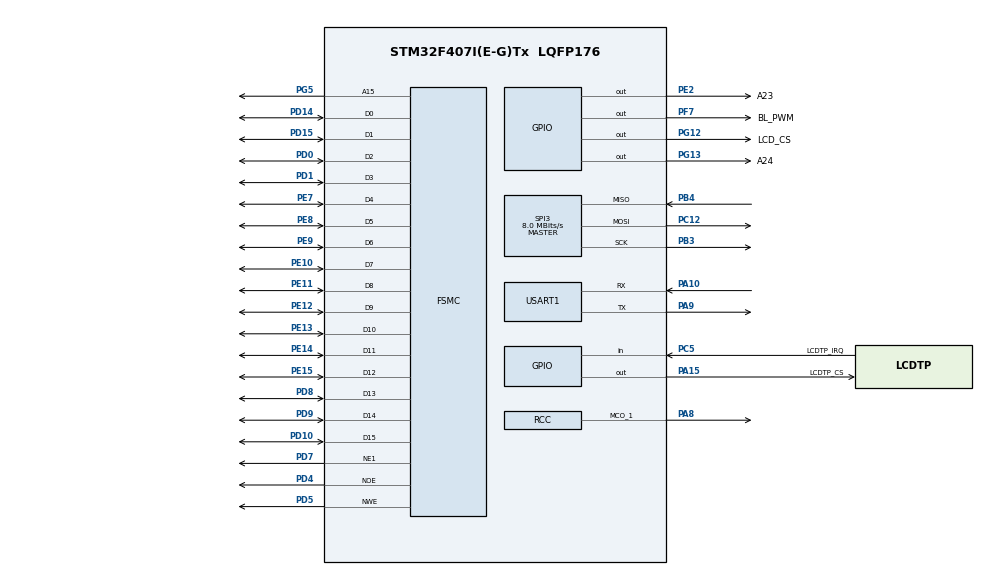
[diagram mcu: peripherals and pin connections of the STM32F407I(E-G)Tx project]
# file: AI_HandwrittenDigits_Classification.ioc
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FSMC.BusTurnAroundDuration1=0
FSMC.DataSetupTime1=40
Mcu.Family=STM32F4
Mcu.Name=STM32F407I(E-G)Tx
Mcu.Package=LQFP176
NVIC.PriorityGroup=NVIC_PRIORITYGROUP_4
NVIC.USART1_IRQn=true\:0\:0\:false\:false\:true\:true\:true
PA10.Mode=Asynchronous
PA10.Signal=USART1_RX
PA15.GPIO_Label=LCDTP_CS
PA15.Signal=GPIO_Output
PA8.Mode=Clock-out-1
PA8.Signal=RCC_MCO_1
PA9.Mode=Asynchronous
PA9.Signal=USART1_TX
PB3.Mode=Full_Duplex_Master
PB3.Signal=SPI3_SCK
PB4.Mode=Full_Duplex_Master
PB4.Signal=SPI3_MISO
PC12.Mode=Full_Duplex_Master
PC12.Signal=SPI3_MOSI
PC5.GPIO_Label=LCDTP_IRQ
PC5.Signal=GPIO_Input
PD0.Signal=FSMC_D2_DA2
PD1.Signal=FSMC_D3_DA3
PD10.Signal=FSMC_D15_DA15
PD14.Signal=FSMC_D0_DA0
PD15.Signal=FSMC_D1_DA1
PD4.Signal=FSMC_NOE
PD5.Signal=FSMC_NWE
PD7.Mode=NorPsramChipSelect1_1
PD7.Signal=FSMC_NE1
PD8.Signal=FSMC_D13_DA13
PD9.Signal=FSMC_D14_DA14
PE10.Signal=FSMC_D7_DA7
PE11.Signal=FSMC_D8_DA8
PE12.Signal=FSMC_D9_DA9
PE13.Signal=FSMC_D10_DA10
PE14.Signal=FSMC_D11_DA11
PE15.Signal=FSMC_D12_DA12
PE2.GPIO_Label=A23
PE2.PinState=GPIO_PIN_SET
PE2.Signal=GPIO_Output
PE7.Signal=FSMC_D4_DA4
PE8.Signal=FSMC_D5_DA5
PE9.Signal=FSMC_D6_DA6
PF7.GPIO_Label=BL_PWM
PF7.PinState=GPIO_PIN_SET
PF7.Signal=GPIO_Output
PG12.GPIO_Label=LCD_CS
PG12.Signal=GPIO_Output
PG13.GPIO_Label=A24
PG13.PinState=GPIO_PIN_SET
PG13.Signal=GPIO_Output
PG5.Signal=FSMC_A15
PH0-OSC_IN.Mode=HSE-External-Oscillator
PH0-OSC_IN.Signal=RCC_OSC_IN
PH1-OSC_OUT.Mode=HSE-External-Oscillator
PH1-OSC_OUT.Signal=RCC_OSC_OUT
ProjectManager.HeapSize=0x200
ProjectManager.StackSize=0x400
ProjectManager.TargetToolchain=STM32CubeIDE
RCC.AHBFreq_Value=16000000
RCC.APB1Freq_Value=16000000
RCC.APB2Freq_Value=16000000
RCC.CortexFreq_Value=16000000
RCC.HSE_VALUE=25000000
RCC.HSI_VALUE=16000000
RCC.LSE_VALUE=32768
RCC.SYSCLKFreq_VALUE=16000000
RCC.VCOOutputFreq_Value=192000000
SH.FSMC_A15.0=FSMC_A15,A15_1
SH.FSMC_D0_DA0.0=FSMC_D0,16b-d1
SH.FSMC_D10_DA10.0=FSMC_D10,16b-d1
SH.FSMC_D11_DA11.0=FSMC_D11,16b-d1
SH.FSMC_D12_DA12.0=FSMC_D12,16b-d1
SH.FSMC_D13_DA13.0=FSMC_D13,16b-d1
SH.FSMC_D14_DA14.0=FSMC_D14,16b-d1
SH.FSMC_D15_DA15.0=FSMC_D15,16b-d1
SH.FSMC_D1_DA1.0=FSMC_D1,16b-d1
SH.FSMC_D2_DA2.0=FSMC_D2,16b-d1
SH.FSMC_D3_DA3.0=FSMC_D3,16b-d1
SH.FSMC_D4_DA4.0=FSMC_D4,16b-d1
SH.FSMC_D5_DA5.0=FSMC_D5,16b-d1
SH.FSMC_D6_DA6.0=FSMC_D6,16b-d1
SH.FSMC_D7_DA7.0=FSMC_D7,16b-d1
SH.FSMC_D8_DA8.0=FSMC_D8,16b-d1
SH.FSMC_D9_DA9.0=FSMC_D9,16b-d1
SH.FSMC_NOE.0=FSMC_NOE,Lcd1
SH.FSMC_NWE.0=FSMC_NWE,Lcd1
SPI3.CalculateBaudRate=8.0 MBits/s
SPI3.Direction=SPI_DIRECTION_2LINES
SPI3.Mode=SPI_MODE_MASTER
SPI3.VirtualType=VM_MASTER
STMicroelectronics.X-CUBE-AI.4.0.0.ApplicationCcArtificialOoIntelligenceJjApplication=ApplicationTemplate
STMicroelectronics.X-CUBE-AI.4.0.0.ArtificialOoIntelligenceJjApplication.cmp_version0=4.0.0
STMicroelectronics.X-CUBE-AI.4.0.0.ArtificialOoIntelligenceJjApplication.component0=Artificial Intelligence
STMicroelectronics.X-CUBE-AI.4.0.0.ArtificialOoIntelligenceJjApplication.description0=AI Application,Application Template
STMicroelectronics.X-CUBE-AI.4.0.0.ArtificialOoIntelligenceJjApplication.diagnostic0=This component requires one or more component from the same or other SW pack to operate correctly
STMicroelectronics.X-CUBE-AI.4.0.0.ArtificialOoIntelligenceJjApplication.documentation0=Documentation/index.html
STMicroelectronics.X-CUBE-AI.4.0.0.ArtificialOoIntelligenceJjApplication.group0=Application
STMicroelectronics.X-CUBE-AI.4.0.0.ArtificialOoIntelligenceJjApplication.paramName0=ApplicationCcArtificialOoIntelligenceJjApplication
STMicroelectronics.X-CUBE-AI.4.0.0.ArtificialOoIntelligenceJjApplication.sevirity0=minor
STMicroelectronics.X-CUBE-AI.4.0.0.ArtificialOoIntelligenceJjApplication.variant0=ApplicationTemplate
STMicroelectronics.X-CUBE-AI.4.0.0.ArtificialOoIntelligenceJjApplication_bundle=Application
STMicroelectronics.X-CUBE-AI.4.0.0.ArtificialOoIntelligenceJjApplication_class=ArtificialOoIntelligence
STMicroelectronics.X-CUBE-AI.4.0.0.ArtificialOoIntelligenceJjApplication_name=X-CUBE-AI
STMicroelectronics.X-CUBE-AI.4.0.0.ArtificialOoIntelligenceJjApplication_size=1
STMicroelectronics.X-CUBE-AI.4.0.0.ArtificialOoIntelligenceJjApplication_vendor=STMicroelectronics
STMicroelectronics.X-CUBE-AI.4.0.0.ArtificialOoIntelligenceJjApplication_version=4.0.0
STMicroelectronics.X-CUBE-AI.4.0.0.ArtificialOoIntelligenceJjXAaCUBEAaAI.cmp_version0=4.0.0
STMicroelectronics.X-CUBE-AI.4.0.0.ArtificialOoIntelligenceJjXAaCUBEAaAI.cmp_version1=4.0.0
STMicroelectronics.X-CUBE-AI.4.0.0.ArtificialOoIntelligenceJjXAaCUBEAaAI.component0=Artificial Intelligence
STMicroelectronics.X-CUBE-AI.4.0.0.ArtificialOoIntelligenceJjXAaCUBEAaAI.component1=Artificial Intelligence
STMicroelectronics.X-CUBE-AI.4.0.0.ArtificialOoIntelligenceJjXAaCUBEAaAI.componentDoc0=nofile
STMicroelectronics.X-CUBE-AI.4.0.0.ArtificialOoIntelligenceJjXAaCUBEAaAI.description0=AI Core,Artificial Intelligence for STM32
STMicroelectronics.X-CUBE-AI.4.0.0.ArtificialOoIntelligenceJjXAaCUBEAaAI.description1=AI Application,Application Template
STMicroelectronics.X-CUBE-AI.4.0.0.ArtificialOoIntelligenceJjXAaCUBEAaAI.diagnostic0=This component should operate correctly.
STMicroelectronics.X-CUBE-AI.4.0.0.ArtificialOoIntelligenceJjXAaCUBEAaAI.diagnostic1=This component requires one or more component from the same or other SW pack to operate correctly
STMicroelectronics.X-CUBE-AI.4.0.0.ArtificialOoIntelligenceJjXAaCUBEAaAI.documentation0=Documentation/index.html
STMicroelectronics.X-CUBE-AI.4.0.0.ArtificialOoIntelligenceJjXAaCUBEAaAI.documentation1=Documentation/index.html
STMicroelectronics.X-CUBE-AI.4.0.0.ArtificialOoIntelligenceJjXAaCUBEAaAI.group0=Core
STMicroelectronics.X-CUBE-AI.4.0.0.ArtificialOoIntelligenceJjXAaCUBEAaAI.group1=Application
STMicroelectronics.X-CUBE-AI.4.0.0.ArtificialOoIntelligenceJjXAaCUBEAaAI.paramName0=XAaCUBEAaAICcArtificialOoIntelligenceJjCore
STMicroelectronics.X-CUBE-AI.4.0.0.ArtificialOoIntelligenceJjXAaCUBEAaAI.paramName1=ApplicationCcArtificialOoIntelligenceJjApplication
STMicroelectronics.X-CUBE-AI.4.0.0.ArtificialOoIntelligenceJjXAaCUBEAaAI.sevirity0=none
STMicroelectronics.X-CUBE-AI.4.0.0.ArtificialOoIntelligenceJjXAaCUBEAaAI.sevirity1=minor
STMicroelectronics.X-CUBE-AI.4.0.0.ArtificialOoIntelligenceJjXAaCUBEAaAI.variant1=ApplicationTemplate
STMicroelectronics.X-CUBE-AI.4.0.0.ArtificialOoIntelligenceJjXAaCUBEAaAI_bundle=X-CUBE-AI
STMicroelectronics.X-CUBE-AI.4.0.0.ArtificialOoIntelligenceJjXAaCUBEAaAI_class=ArtificialOoIntelligence
STMicroelectronics.X-CUBE-AI.4.0.0.ArtificialOoIntelligenceJjXAaCUBEAaAI_name=X-CUBE-AI
STMicroelectronics.X-CUBE-AI.4.0.0.ArtificialOoIntelligenceJjXAaCUBEAaAI_size=2
STMicroelectronics.X-CUBE-AI.4.0.0.ArtificialOoIntelligenceJjXAaCUBEAaAI_vendor=STMicroelectronics
STMicroelectronics.X-CUBE-AI.4.0.0.ArtificialOoIntelligenceJjXAaCUBEAaAI_version=4.0.0
STMicroelectronics.X-CUBE-AI.4.0.0.LatestDirectoryUsed-9fa8add1d17a329f3bc8a1bb6cbe9676fff839fc02631deaaa17ee1fde3ea9c4=C\:\\Users\\Prakashs\\Downloads
STMicroelectronics.X-CUBE-AI.4.0.0.ModelActualCompression-9fa8add1d17a329f3bc8a1bb6cbe9676fff839fc02631deaaa17ee1fde3ea9c4=0.0
STMicroelectronics.X-CUBE-AI.4.0.0.ModelCompression-9fa8add1d17a329f3bc8a1bb6cbe9676fff839fc02631deaaa17ee1fde3ea9c4=1
STMicroelectronics.X-CUBE-AI.4.0.0.ModelFlashOccupation-9fa8add1d17a329f3bc8a1bb6cbe9676fff839fc02631deaaa17ee1fde3ea9c4=407080
STMicroelectronics.X-CUBE-AI.4.0.0.ModelHashList=9fa8add1d17a329f3bc8a1bb6cbe9676fff839fc02631deaaa17ee1fde3ea9c4
STMicroelectronics.X-CUBE-AI.4.0.0.ModelKind-9fa8add1d17a329f3bc8a1bb6cbe9676fff839fc02631deaaa17ee1fde3ea9c4=KERAS
STMicroelectronics.X-CUBE-AI.4.0.0.ModelMacc-9fa8add1d17a329f3bc8a1bb6cbe9676fff839fc02631deaaa17ee1fde3ea9c4=101910
STMicroelectronics.X-CUBE-AI.4.0.0.ModelName-9fa8add1d17a329f3bc8a1bb6cbe9676fff839fc02631deaaa17ee1fde3ea9c4=digitclassification
STMicroelectronics.X-CUBE-AI.4.0.0.ModelNameList=digitclassification
STMicroelectronics.X-CUBE-AI.4.0.0.ModelRamOccupation-9fa8add1d17a329f3bc8a1bb6cbe9676fff839fc02631deaaa17ee1fde3ea9c4=552
STMicroelectronics.X-CUBE-AI.4.0.0.ModelStructureFile-9fa8add1d17a329f3bc8a1bb6cbe9676fff839fc02631deaaa17ee1fde3ea9c4=C\:\\Users\\Prakashs\\Downloads\\model_CNN.h5
STMicroelectronics.X-CUBE-AI.4.0.0.ModelType-9fa8add1d17a329f3bc8a1bb6cbe9676fff839fc02631deaaa17ee1fde3ea9c4=Model and Topology
STMicroelectronics.X-CUBE-AI.4.0.0.ModelWeightFile-9fa8add1d17a329f3bc8a1bb6cbe9676fff839fc02631deaaa17ee1fde3ea9c4=C\:\\Users\\Prakashs\\Downloads\\model_CNN.json
STMicroelectronics.X-CUBE-AI.4.0.0.XAaCUBEAaAICcArtificialOoIntelligenceJjCore=true
STMicroelectronics.X-CUBE-AI.4.0.0_ArtificialOoIntelligenceJjApplication_RteComponent0=\#define AI_ApplicationTemplate
STMicroelectronics.X-CUBE-AI.4.0.0_ArtificialOoIntelligenceJjApplication_RteComponentsize=1
STMicroelectronics.X-CUBE-AI.4.0.0_ArtificialOoIntelligenceJjXAaCUBEAaAI_RteComponentsize=0
STMicroelectronics.X-CUBE-AI.4.0.0_MwName0=X-CUBE-AI
STMicroelectronics.X-CUBE-AI.4.0.0_MwName1=Application
STMicroelectronics.X-CUBE-AI.4.0.0_NumberOfMw=2
STMicroelectronics.X-CUBE-AI.4.0.0_description=Artificial Intelligence
STMicroelectronics.X-CUBE-AI.4.0.0_license=SLA0048.txt
USART1.VirtualMode=VM_ASYNC
VP_CRC_VS_CRC.Mode=CRC_Activate
VP_STMicroelectronics.X-CUBE-AI_VS_ArtificialOoIntelligenceJjApplication_4.0.0.Mode=ArtificialOoIntelligenceJjApplication
VP_STMicroelectronics.X-CUBE-AI_VS_ArtificialOoIntelligenceJjXAaCUBEAaAI_4.0.0.Mode=ArtificialOoIntelligenceJjXAaCUBEAaAI
board=custom

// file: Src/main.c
/* USER CODE BEGIN Header */
/**
  ******************************************************************************
  * @file           : main.c
  * @brief          : Main program body
  ******************************************************************************
  * @attention
  *
  * <h2><center>&copy; Copyright (c) 2019 STMicroelectronics.
  * All rights reserved.</center></h2>
  *
  * This software component is licensed by ST under BSD 3-Clause license,
  * the "License"; You may not use this file except in compliance with the
  * License. You may obtain a copy of the License at:
  *                        opensource.org/licenses/BSD-3-Clause
  *
  ******************************************************************************
  */
/* USER CODE END Header */

#include "main.h"
#include "app_x-cube-ai.h"

/* USER CODE BEGIN Includes */
#include "stm32_lcd_bsp.h"
#include "touch_panel.h"
/* USER CODE END Includes */

/* USER CODE BEGIN PM */
#ifdef __GNUC__
  /* With GCC/RAISONANCE, small printf (option LD Linker->Libraries->Small printf
     set to 'Yes') calls __io_putchar() */
  #define PUTCHAR_PROTOTYPE int __io_putchar(int ch)
#else
  #define PUTCHAR_PROTOTYPE int fputc(int ch, FILE *f)
#endif /* __GNUC__ */
/* USER CODE END PM */

CRC_HandleTypeDef hcrc;

SPI_HandleTypeDef hspi3;

UART_HandleTypeDef huart1;

SRAM_HandleTypeDef hsram1;

/* USER CODE BEGIN PV */
uint16_t original_image[168*168];
uint8_t grayscale_image[28*28];
uint16_t resized_image[28*28];
uint16_t *ptToImage = &original_image;
uint16_t drawMenuNeeded = 0;
/* USER CODE END PV */

void SystemClock_Config(void);
static void MX_GPIO_Init(void);
static void MX_CRC_Init(void);
static void MX_FSMC_Init(void);
static void MX_SPI3_Init(void);
static void MX_USART1_UART_Init(void);
/* USER CODE BEGIN PFP */
void loadImageIntoMemory();
void convert_8Bit_Grayscale(uint16_t* buffer);
void ImageResize(uint8_t *srcImage, uint32_t srcW, uint32_t srcH,
                 uint32_t pixelSize, uint32_t roiX, uint32_t roiY,
                 uint32_t roiW, uint32_t roiH,  uint8_t *dstImage,
                 uint32_t dstW, uint32_t dstH);
void drawMenu();
/* USER CODE END PFP */

int main(void)
{
  /* USER CODE BEGIN 1 */
	uint16_t linenum = 0;
  /* USER CODE END 1 */

  /* MCU Configuration--------------------------------------------------------*/

  /* Reset of all peripherals, Initializes the Flash interface and the Systick. */
  HAL_Init();

  /* Configure the system clock */
  SystemClock_Config();

  /* Initialize all configured peripherals */
  MX_GPIO_Init();
  MX_CRC_Init();
  MX_FSMC_Init();
  MX_SPI3_Init();
  MX_USART1_UART_Init();
  MX_X_CUBE_AI_Init();
  /* USER CODE BEGIN 2 */
  /* Initialize the LCD */
  BSP_LCD_Init();
    /* Enable the LCD */
  BSP_LCD_DisplayOn();
    /* Touch Panel configuration */
  printf("LCD is on");
  TouchPanel_Calibrate();
  drawMenu();
  printf("touch calibrated");
  /* USER CODE END 2 */

  /* Infinite loop */
  while (1)
  {
    /* USER CODE BEGIN 3 */

	  	  	getDisplayPoint(&display, Read_Ads7846(), &matrix );
	  	    if(((display.y < 190) && (display.y >= 2)))
	  	    {
	  	      if((display.x >= 318) || (display.x < 2))
	  	      {}
	  	      else
	  	      {
	  	        BSP_LCD_FillCircle(display.x, display.y, 2);
	  	      }
	  	    }

	  	    if((HAL_GPIO_ReadPin(Push_button_GPIO_Port, Push_button_Pin))==GPIO_PIN_RESET)
	  	    {
	  	    	loadImageIntoMemory();
	  	    	ImageResize((uint8_t*)original_image, 168, 168, 2, 0, 0, 0, 0,(uint8_t*)resized_image, 28, 28);
	  	    	convert_8Bit_Grayscale((uint16_t*)resized_image);
	  	    	MX_X_CUBE_AI_Process();
	  	    }
  }
  /* USER CODE END 3 */
}

void SystemClock_Config(void)
{
	 RCC_OscInitTypeDef RCC_OscInitStruct;
	  RCC_ClkInitTypeDef RCC_ClkInitStruct;

	    /**Configure the main internal regulator output voltage
	    */
	  __HAL_RCC_PWR_CLK_ENABLE();

	  __HAL_PWR_VOLTAGESCALING_CONFIG(PWR_REGULATOR_VOLTAGE_SCALE1);

	    /**Initializes the CPU, AHB and APB busses clocks
	    */
	  RCC_OscInitStruct.OscillatorType = RCC_OSCILLATORTYPE_HSI;
	  RCC_OscInitStruct.HSIState = RCC_HSI_ON;
	  RCC_OscInitStruct.HSICalibrationValue = 16;
	  RCC_OscInitStruct.PLL.PLLState = RCC_PLL_ON;
	  RCC_OscInitStruct.PLL.PLLSource = RCC_PLLSOURCE_HSI;
	  RCC_OscInitStruct.PLL.PLLM = 8;
	  RCC_OscInitStruct.PLL.PLLN = 168;
	  RCC_OscInitStruct.PLL.PLLP = RCC_PLLP_DIV2;
	  RCC_OscInitStruct.PLL.PLLQ = 4;
	  if (HAL_RCC_OscConfig(&RCC_OscInitStruct) != HAL_OK)
	  {
	    Error_Handler();
	  }

	    /**Initializes the CPU, AHB and APB busses clocks
	    */
	  RCC_ClkInitStruct.ClockType = RCC_CLOCKTYPE_HCLK|RCC_CLOCKTYPE_SYSCLK
	                              |RCC_CLOCKTYPE_PCLK1|RCC_CLOCKTYPE_PCLK2;
	  RCC_ClkInitStruct.SYSCLKSource = RCC_SYSCLKSOURCE_PLLCLK;
	  RCC_ClkInitStruct.AHBCLKDivider = RCC_SYSCLK_DIV1;
	  RCC_ClkInitStruct.APB1CLKDivider = RCC_HCLK_DIV4;
	  RCC_ClkInitStruct.APB2CLKDivider = RCC_HCLK_DIV2;

	  if (HAL_RCC_ClockConfig(&RCC_ClkInitStruct, FLASH_LATENCY_5) != HAL_OK)
	  {
	    Error_Handler();
	  }

	    /**Configure the Systick interrupt time
	    */
	  HAL_SYSTICK_Config(HAL_RCC_GetHCLKFreq()/1000);

	    /**Configure the Systick
	    */
	  HAL_SYSTICK_CLKSourceConfig(SYSTICK_CLKSOURCE_HCLK);

	  /* SysTick_IRQn interrupt configuration */
	  HAL_NVIC_SetPriority(SysTick_IRQn, 0, 0);
}

static void MX_CRC_Init(void)
{

  hcrc.Instance = CRC;
  if (HAL_CRC_Init(&hcrc) != HAL_OK)
  {
    Error_Handler();
  }

}

static void MX_SPI3_Init(void)
{

  /* SPI3 parameter configuration*/
	 hspi3.Instance = SPI3;
	  hspi3.Init.Mode = SPI_MODE_MASTER;
	  hspi3.Init.Direction = SPI_DIRECTION_2LINES;
	  hspi3.Init.DataSize = SPI_DATASIZE_8BIT;
	  hspi3.Init.CLKPolarity = SPI_POLARITY_LOW;
	  hspi3.Init.CLKPhase = SPI_PHASE_1EDGE;
	  hspi3.Init.NSS = SPI_NSS_SOFT;
	  hspi3.Init.BaudRatePrescaler = SPI_BAUDRATEPRESCALER_32;
	  hspi3.Init.FirstBit = SPI_FIRSTBIT_MSB;
	  hspi3.Init.TIMode = SPI_TIMODE_DISABLE;
	  hspi3.Init.CRCCalculation = SPI_CRCCALCULATION_DISABLE;
	  hspi3.Init.CRCPolynomial = 10;
	  if (HAL_SPI_Init(&hspi3) != HAL_OK)
	  {
	    Error_Handler();
	  }

}

static void MX_USART1_UART_Init(void)
{

	  huart1.Instance = USART1;
	  huart1.Init.BaudRate = 115200;
	  huart1.Init.WordLength = UART_WORDLENGTH_8B;
	  huart1.Init.StopBits = UART_STOPBITS_1;
	  huart1.Init.Parity = UART_PARITY_NONE;
	  huart1.Init.Mode = UART_MODE_TX_RX;
	  huart1.Init.HwFlowCtl = UART_HWCONTROL_NONE;
	  huart1.Init.OverSampling = UART_OVERSAMPLING_16;
	  if (HAL_UART_Init(&huart1) != HAL_OK)
	  {
	    Error_Handler();
	  }

}

static void MX_GPIO_Init(void)
{
	 GPIO_InitTypeDef GPIO_InitStruct;

	  /* GPIO Ports Clock Enable */
	  __HAL_RCC_GPIOE_CLK_ENABLE();
	  __HAL_RCC_GPIOF_CLK_ENABLE();
	  __HAL_RCC_GPIOH_CLK_ENABLE();
	  __HAL_RCC_GPIOC_CLK_ENABLE();
	  __HAL_RCC_GPIOD_CLK_ENABLE();
	  __HAL_RCC_GPIOG_CLK_ENABLE();
	  __HAL_RCC_GPIOA_CLK_ENABLE();
	  __HAL_RCC_GPIOB_CLK_ENABLE();

	  /*Configure GPIO pin Output Level */
	  HAL_GPIO_WritePin(A23_GPIO_Port, A23_Pin, GPIO_PIN_SET);

	  /*Configure GPIO pin Output Level */
	  HAL_GPIO_WritePin(BL_PWM_GPIO_Port, BL_PWM_Pin, GPIO_PIN_SET);

	  /*Configure GPIO pin Output Level */
	  HAL_GPIO_WritePin(LCDTP_CS_GPIO_Port, LCDTP_CS_Pin, GPIO_PIN_RESET);

	  /*Configure GPIO pin Output Level */
	  HAL_GPIO_WritePin(LCD_CS_GPIO_Port, LCD_CS_Pin, GPIO_PIN_RESET);

	  /*Configure GPIO pin Output Level */
	  HAL_GPIO_WritePin(A24_GPIO_Port, A24_Pin, GPIO_PIN_SET);

	  /*Configure GPIO pin : PtPin */
	  GPIO_InitStruct.Pin = A23_Pin;
	  GPIO_InitStruct.Mode = GPIO_MODE_OUTPUT_PP;
	  GPIO_InitStruct.Pull = GPIO_NOPULL;
	  GPIO_InitStruct.Speed = GPIO_SPEED_FREQ_LOW;
	  HAL_GPIO_Init(A23_GPIO_Port, &GPIO_InitStruct);

	  /*Configure GPIO pin : PtPin */
	  GPIO_InitStruct.Pin = BL_PWM_Pin;
	  GPIO_InitStruct.Mode = GPIO_MODE_OUTPUT_PP;
	  GPIO_InitStruct.Pull = GPIO_NOPULL;
	  GPIO_InitStruct.Speed = GPIO_SPEED_FREQ_LOW;
	  HAL_GPIO_Init(BL_PWM_GPIO_Port, &GPIO_InitStruct);

	  /*Configure GPIO pin : PtPin */
	  GPIO_InitStruct.Pin = LCDTP_IRQ_Pin;
	  GPIO_InitStruct.Mode = GPIO_MODE_INPUT;
	  GPIO_InitStruct.Pull = GPIO_NOPULL;
	  HAL_GPIO_Init(LCDTP_IRQ_GPIO_Port, &GPIO_InitStruct);

	  /*Configure GPIO pin : PtPin */
	  GPIO_InitStruct.Pin = LCDTP_CS_Pin;
	  GPIO_InitStruct.Mode = GPIO_MODE_OUTPUT_PP;
	  GPIO_InitStruct.Pull = GPIO_NOPULL;
	  GPIO_InitStruct.Speed = GPIO_SPEED_FREQ_LOW;
	  HAL_GPIO_Init(LCDTP_CS_GPIO_Port, &GPIO_InitStruct);

	  /*Configure GPIO pins : PGPin PGPin */
	  GPIO_InitStruct.Pin = LCD_CS_Pin|A24_Pin;
	  GPIO_InitStruct.Mode = GPIO_MODE_OUTPUT_PP;
	  GPIO_InitStruct.Pull = GPIO_NOPULL;
	  GPIO_InitStruct.Speed = GPIO_SPEED_FREQ_LOW;
	  HAL_GPIO_Init(GPIOG, &GPIO_InitStruct);

}

/* FSMC initialization function */
static void MX_FSMC_Init(void)
{

	  FSMC_NORSRAM_TimingTypeDef Timing;

	  /** Perform the SRAM1 memory initialization sequence
	  */
	  hsram1.Instance = FSMC_NORSRAM_DEVICE;
	  hsram1.Extended = FSMC_NORSRAM_EXTENDED_DEVICE;
	  /* hsram1.Init */
	  hsram1.Init.NSBank = FSMC_NORSRAM_BANK1;
	  hsram1.Init.DataAddressMux = FSMC_DATA_ADDRESS_MUX_DISABLE;
	  hsram1.Init.MemoryType = FSMC_MEMORY_TYPE_SRAM;
	  hsram1.Init.MemoryDataWidth = FSMC_NORSRAM_MEM_BUS_WIDTH_16;
	  hsram1.Init.BurstAccessMode = FSMC_BURST_ACCESS_MODE_DISABLE;
	  hsram1.Init.WaitSignalPolarity = FSMC_WAIT_SIGNAL_POLARITY_LOW;
	  hsram1.Init.WrapMode = FSMC_WRAP_MODE_DISABLE;
	  hsram1.Init.WaitSignalActive = FSMC_WAIT_TIMING_BEFORE_WS;
	  hsram1.Init.WriteOperation = FSMC_WRITE_OPERATION_ENABLE;
	  hsram1.Init.WaitSignal = FSMC_WAIT_SIGNAL_DISABLE;
	  hsram1.Init.ExtendedMode = FSMC_EXTENDED_MODE_DISABLE;
	  hsram1.Init.AsynchronousWait = FSMC_ASYNCHRONOUS_WAIT_DISABLE;
	  hsram1.Init.WriteBurst = FSMC_WRITE_BURST_DISABLE;
	  hsram1.Init.PageSize = FSMC_PAGE_SIZE_NONE;
	  /* Timing */
	  Timing.AddressSetupTime = 4;
	  Timing.AddressHoldTime = 15;
	  Timing.DataSetupTime = 40;
	  Timing.BusTurnAroundDuration = 0;
	  Timing.CLKDivision = 16;
	  Timing.DataLatency = 17;
	  Timing.AccessMode = FSMC_ACCESS_MODE_A;
	  /* ExtTiming */

	  if (HAL_SRAM_Init(&hsram1, &Timing, NULL) != HAL_OK)
	  {
	    Error_Handler();
	  }

}

/* USER CODE BEGIN 4 */
/**
  * @brief  Retargets the C library printf function to the USART.
  * @param  None
  * @retval None
  */
PUTCHAR_PROTOTYPE
{
  /* write a character to the uart1 and Loop until the end of transmission */
  HAL_UART_Transmit(&huart1, (uint8_t *)&ch, 1, 0xFFFF);

  return ch;
}

/**
  * @brief  Performs image (or selected Region Of Interest) resizing using bilinear interpolation
  * @param  srcImage     Pointer to source image buffer
  * @param  srcW         Source image width
  * @param  srcH         Source image height
  * @param  pixelSize    Number of bytes per pixel
  * @param  roiX         Region Of Interest x starting location
  * @param  roiY         Region Of Interest y starting location
  * @param  roiW         Region Of Interest width
  * @param  roiH         Region Of Interest height
  * @param  dstImage     Pointer to destination image buffer
  * @param  dstW         Destination image width
  * @param  dstH         Destination image height
  * @retval void         None
  */
void ImageResize(uint8_t *srcImage, uint32_t srcW, uint32_t srcH,
                 uint32_t pixelSize, uint32_t roiX, uint32_t roiY,
                 uint32_t roiW, uint32_t roiH,  uint8_t *dstImage,
                 uint32_t dstW, uint32_t dstH)
{
  int32_t srcStride;
  float widthRatio;
  float heightRatio;

  int32_t maxWidth;
  int32_t maxHeight;

  float srcX, srcY, dX1, dY1, dX2, dY2;
  int32_t dstX1, srcY1, dstX2, srcY2;

  uint8_t *tmp1, *tmp2;
  uint8_t *p1, *p2, *p3, *p4;

  int32_t offset1;
  int32_t offset2;

  srcStride = pixelSize * srcW;

  widthRatio = ((roiW ? roiW : srcW) / (float) dstW);
  heightRatio = ((roiH ? roiH : srcH) / (float) dstH);

  /* Get horizontal and vertical limits. */
  maxWidth = (roiW ? roiW : srcW) - 1;
  maxHeight = (roiH ? roiH : srcH) - 1;

  for (int32_t y = 0; y < dstH; y++)
  {
    /* Get Y from source. */
    srcY = ((float) y * heightRatio) + roiY;
    srcY1 = (int32_t) srcY;
    srcY2 = (srcY1 == maxHeight) ? srcY1 : srcY1 + 1;
    dY1 = srcY - (float) srcY1;
    dY2 = 1.0f - dY1;

    /* Calculates the pointers to the two needed lines of the source. */
    tmp1 = srcImage + srcY1 * srcStride;
    tmp2 = srcImage + srcY2 * srcStride;

    for (int32_t x = 0; x < dstW; x++)
    {
      /* Get X from source. */
      srcX = x * widthRatio + roiX;
      dstX1 = (int32_t) srcX;
      dstX2 = (dstX1 == maxWidth) ? dstX1 : dstX1 + 1;
      dX1 = srcX - /*(float32)*/dstX1;
      dX2 = 1.0f - dX1;

      /* Calculates the four points (p1,p2, p3, p4) of the source. */
      offset1 = dstX1 * pixelSize;
      offset2 = dstX2 * pixelSize;
      p1 = tmp1 + offset1;
      p2 = tmp1 + offset2;
      p3 = tmp2 + offset1;
      p4 = tmp2 + offset2;
      /* For each channel, interpolate the four points. */
      for (int32_t ch = 0; ch < pixelSize; ch++, dstImage++, p1++, p2++, p3++, p4++)
      {
        *dstImage = (uint8_t)(dY2 * (dX2 * (*p1) + dX1 * (*p2)) + dY1 * (dX2 * (*p3) + dX1 * (*p4)));
      }
    }
  }
}

// Convert to 8 bit grayscale
void convert_8Bit_Grayscale(uint16_t* buffer)
{
	for(int16_t i=0; i< 784; i++)
		      {
		   	   uint16_t pixel = *buffer;
		   	   uint8_t red = ((pixel & 0xF800)>>11);
		   	   uint8_t green = ((pixel & 0x07E0)>>5);
		   	   uint8_t blue = (pixel & 0x001F);
		   	   grayscale_image[i] = (0.2126 * red) + (0.7152 * green / 2.0) + (0.0722 * blue);
		   	   if(grayscale_image[i] == 0x00)
		   		   grayscale_image[i] = 0XFF;
		   	   else if(grayscale_image[i]==0x1F)
		   		   grayscale_image[i]=0X00;
		   	   buffer++;
		      }
}

// Draw the Menu screen
void drawMenu()
{
	  BSP_LCD_Clear(LCD_COLOR_WHITE);
	  BSP_LCD_SetTextColor(LCD_COLOR_BLACK);
	  BSP_LCD_DrawHLine(50,30,170);
	  BSP_LCD_DrawHLine(50,200,170);
	  BSP_LCD_DrawVLine(50, 30, 170);
	  BSP_LCD_DrawVLine(220, 30, 170);
	  BSP_LCD_SetFont(&Font24);
}

// Load LCD Pixel values to Memory
void loadImageIntoMemory()
{
	for(uint16_t i=31; i<199; i++)
	{
		for(uint16_t j=51;j<219;j++)
		{
			*ptToImage = ili9325_ReadPixel(j, i);
			ptToImage++;
		}
	}
	BSP_LCD_SetTextColor(LCD_COLOR_BLACK);
	BSP_LCD_SetFont(&Font24);
	ili9325_SetCursor(0, 0);
}

/* USER CODE END 4 */

void Error_Handler(void)
{
}

/************************ (C) COPYRIGHT STMicroelectronics *****END OF FILE****/
